VERSION 5.7 ;
  NOWIREEXTENSIONATPIN ON ;
  DIVIDERCHAR "/" ;
  BUSBITCHARS "[]" ;
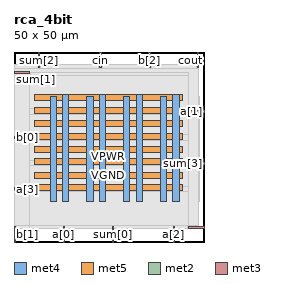
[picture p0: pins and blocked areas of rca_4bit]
MACRO rca_4bit
  CLASS BLOCK ;
  FOREIGN rca_4bit ;
  ORIGIN 0.000 0.000 ;
  SIZE 50.000 BY 50.000 ;
  PIN VGND
    DIRECTION INOUT ;
    USE GROUND ;
    PORT
      LAYER met4 ;
        RECT 12.850 10.640 14.450 38.760 ;
    END
    PORT
      LAYER met4 ;
        RECT 22.510 10.640 24.110 38.760 ;
    END
    PORT
      LAYER met4 ;
        RECT 32.170 10.640 33.770 38.760 ;
    END
    PORT
      LAYER met4 ;
        RECT 41.830 10.640 43.430 38.760 ;
    END
    PORT
      LAYER met5 ;
        RECT 5.280 16.775 44.400 18.375 ;
    END
    PORT
      LAYER met5 ;
        RECT 5.280 23.570 44.400 25.170 ;
    END
    PORT
      LAYER met5 ;
        RECT 5.280 30.365 44.400 31.965 ;
    END
    PORT
      LAYER met5 ;
        RECT 5.280 37.160 44.400 38.760 ;
    END
  END VGND
  PIN VPWR
    DIRECTION INOUT ;
    USE POWER ;
    PORT
      LAYER met4 ;
        RECT 9.550 10.640 11.150 38.320 ;
    END
    PORT
      LAYER met4 ;
        RECT 19.210 10.640 20.810 38.320 ;
    END
    PORT
      LAYER met4 ;
        RECT 28.870 10.640 30.470 38.320 ;
    END
    PORT
      LAYER met4 ;
        RECT 38.530 10.640 40.130 38.320 ;
    END
    PORT
      LAYER met5 ;
        RECT 5.280 13.475 44.400 15.075 ;
    END
    PORT
      LAYER met5 ;
        RECT 5.280 20.270 44.400 21.870 ;
    END
    PORT
      LAYER met5 ;
        RECT 5.280 27.065 44.400 28.665 ;
    END
    PORT
      LAYER met5 ;
        RECT 5.280 33.860 44.400 35.460 ;
    END
  END VPWR
  PIN a[0]
    DIRECTION INPUT ;
    USE SIGNAL ;
    ANTENNAGATEAREA 0.196500 ;
    PORT
      LAYER met2 ;
        RECT 12.970 0.000 13.250 4.000 ;
    END
  END a[0]
  PIN a[1]
    DIRECTION INPUT ;
    USE SIGNAL ;
    ANTENNAGATEAREA 0.196500 ;
    PORT
      LAYER met3 ;
        RECT 46.000 34.040 50.000 34.640 ;
    END
  END a[1]
  PIN a[2]
    DIRECTION INPUT ;
    USE SIGNAL ;
    ANTENNAGATEAREA 0.196500 ;
    PORT
      LAYER met2 ;
        RECT 41.950 0.000 42.230 4.000 ;
    END
  END a[2]
  PIN a[3]
    DIRECTION INPUT ;
    USE SIGNAL ;
    ANTENNAGATEAREA 0.196500 ;
    PORT
      LAYER met3 ;
        RECT 0.000 13.640 4.000 14.240 ;
    END
  END a[3]
  PIN b[0]
    DIRECTION INPUT ;
    USE SIGNAL ;
    ANTENNAGATEAREA 0.196500 ;
    PORT
      LAYER met3 ;
        RECT 0.000 27.240 4.000 27.840 ;
    END
  END b[0]
  PIN b[1]
    DIRECTION INPUT ;
    USE SIGNAL ;
    ANTENNAGATEAREA 0.196500 ;
    PORT
      LAYER met2 ;
        RECT 0.090 0.000 0.370 4.000 ;
    END
  END b[1]
  PIN b[2]
    DIRECTION INPUT ;
    USE SIGNAL ;
    ANTENNAGATEAREA 0.196500 ;
    PORT
      LAYER met2 ;
        RECT 35.510 46.000 35.790 50.000 ;
    END
  END b[2]
  PIN b[3]
    DIRECTION INPUT ;
    USE SIGNAL ;
    ANTENNAGATEAREA 0.196500 ;
    PORT
      LAYER met3 ;
        RECT 46.000 3.440 50.000 4.040 ;
    END
  END b[3]
  PIN cin
    DIRECTION INPUT ;
    USE SIGNAL ;
    ANTENNAGATEAREA 0.196500 ;
    PORT
      LAYER met2 ;
        RECT 22.630 46.000 22.910 50.000 ;
    END
  END cin
  PIN cout
    DIRECTION OUTPUT TRISTATE ;
    USE SIGNAL ;
    ANTENNADIFFAREA 0.795200 ;
    PORT
      LAYER met2 ;
        RECT 48.390 46.000 48.670 50.000 ;
    END
  END cout
  PIN sum[0]
    DIRECTION OUTPUT TRISTATE ;
    USE SIGNAL ;
    ANTENNADIFFAREA 0.795200 ;
    PORT
      LAYER met2 ;
        RECT 25.850 0.000 26.130 4.000 ;
    END
  END sum[0]
  PIN sum[1]
    DIRECTION OUTPUT TRISTATE ;
    USE SIGNAL ;
    ANTENNADIFFAREA 0.795200 ;
    PORT
      LAYER met3 ;
        RECT 0.000 44.240 4.000 44.840 ;
    END
  END sum[1]
  PIN sum[2]
    DIRECTION OUTPUT TRISTATE ;
    USE SIGNAL ;
    ANTENNADIFFAREA 0.795200 ;
    PORT
      LAYER met2 ;
        RECT 6.530 46.000 6.810 50.000 ;
    END
  END sum[2]
  PIN sum[3]
    DIRECTION OUTPUT TRISTATE ;
    USE SIGNAL ;
    ANTENNADIFFAREA 0.445500 ;
    PORT
      LAYER met3 ;
        RECT 46.000 20.440 50.000 21.040 ;
    END
  END sum[3]
  OBS
      LAYER li1 ;
        RECT 5.520 10.795 44.160 38.165 ;
      LAYER met1 ;
        RECT 0.070 10.640 48.690 38.320 ;
      LAYER met2 ;
        RECT 0.100 45.720 6.250 46.650 ;
        RECT 7.090 45.720 22.350 46.650 ;
        RECT 23.190 45.720 35.230 46.650 ;
        RECT 36.070 45.720 48.110 46.650 ;
        RECT 0.100 4.280 48.660 45.720 ;
        RECT 0.650 3.555 12.690 4.280 ;
        RECT 13.530 3.555 25.570 4.280 ;
        RECT 26.410 3.555 41.670 4.280 ;
        RECT 42.510 3.555 48.660 4.280 ;
      LAYER met3 ;
        RECT 4.400 43.840 46.000 44.705 ;
        RECT 4.000 35.040 46.000 43.840 ;
        RECT 4.000 33.640 45.600 35.040 ;
        RECT 4.000 28.240 46.000 33.640 ;
        RECT 4.400 26.840 46.000 28.240 ;
        RECT 4.000 21.440 46.000 26.840 ;
        RECT 4.000 20.040 45.600 21.440 ;
        RECT 4.000 14.640 46.000 20.040 ;
        RECT 4.400 13.240 46.000 14.640 ;
        RECT 4.000 4.440 46.000 13.240 ;
        RECT 4.000 3.575 45.600 4.440 ;
  END
END rca_4bit
END LIBRARY

